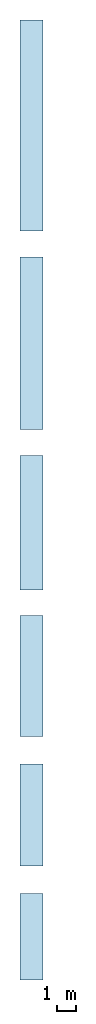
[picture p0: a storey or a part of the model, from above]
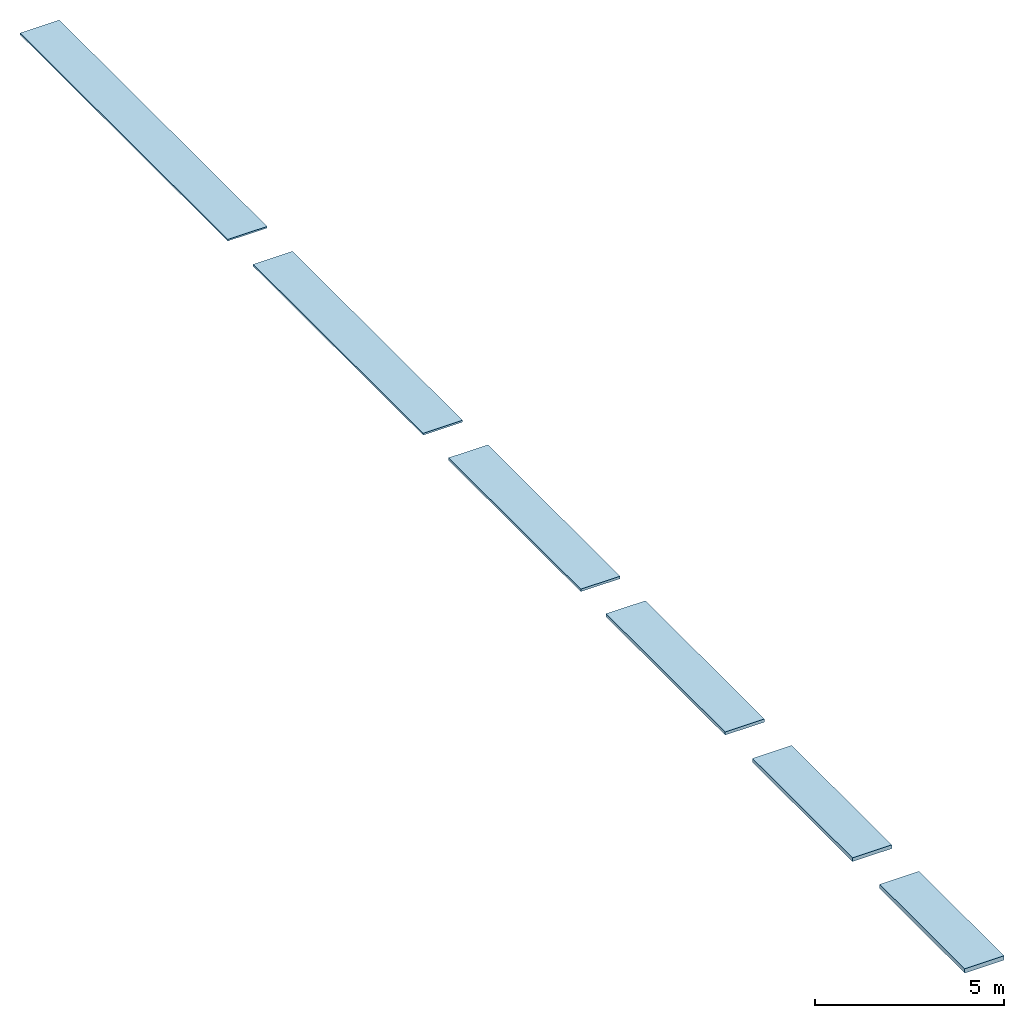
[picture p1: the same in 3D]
Properties of the parts of a building model (IFC2X3)

# File
Description: ViewDefinition [CoordinationView_V2.0]
File name: 0001
Time: 2018-02-28T13:13:18
Written by: The EXPRESS Data Manager Version 5.02.0100.07 : 28 Aug 2013
Made in: 20140606_1530(x64) - Exporter 15.6.0.0 - Alternate UI 15.6.0.0
Comment: STEP Physical File produced by: The EXPRESS Data Manager Version 5.02.0100.07 : 28 Aug 2013 * Module: EDMstepFileFactory/EDMstandAlone * Creation date: Wed Feb 28 13:13:18 2018 * Host: BRUTUS-02 * Database: C:\Users\MIGUEL~1\AppData\Local\Temp\{DA6E0581-9F91-44CB-83B0-A4054EFE4921}\ifc * Database version: 5507 * Database creation date: Wed Feb 28 13:13:18 2018 * Schema: IFC2X3 * Model: DataRepository.ifc * Model creation date: Wed Feb 28 13:13:18 2018 * Header model: DataRepository.ifc_HeaderModel * Header model creation date: Wed Feb 28 13:13:18 2018 * EDMuser: sdai-user * EDMgroup: sdai-group * License ID and type: 5605 : Permanent license. Expiry date: * EDMstepFileFactory options: 020000

# IfcProject, 0001
LongName: Project Name; Phase: Project Status

# IfcSite, Default
RefLatitude: 42, 21, 30, 344238; RefLongitude: -71, -3, -35, -194702; RefElevation: 0 mm
Other - Category: Project Information; Client Name: Owner; Project Address: ## Street City, State Zip; Project Issue Date: Issue Date; Project Name: Project Name; Project Number: 0001; Project Status: Project Status

# IfcBuilding
Pset_BuildingCommon - NumberOfStoreys: 1
Other - Category: Project Information; Client Name: Owner; Project Address: ## Street City, State Zip; Project Issue Date: Issue Date; Project Name: Project Name; Project Number: 0001; Project Status: Project Status

# IfcBuildingStorey, Референтни ниво
LongName: Референтни ниво; Elevation: 0 mm
Other - Category: Levels; Family Name: Level; Family: Level: 8mm Head; Family and Type: Level: 8mm Head; Type: Level: 8mm Head; Type Id: Level: 8mm Head
Constraints - Elevation: 0 mm; Elevation Base: Project Base Point
Dimensions - Computation Height: 0 mm
Identity Data - Building Story: yes; Name: Референтни ниво; Structural: no; Type Name: 8mm Head
Graphics - Color: 0; Line Pattern: Center; Line Weight: 1; Symbol at End 1 Default: no; Symbol at End 2 Default: yes

# IfcRoof: Basic Roof:Knauf Insulation - Unifit 035 - 100 mm - 100 x 6300 x 1200 mm, Basic Roof:Knauf Insulation - Unifit 035 - 100 mm - 100 x 6300 x 1200 mm:206765
In: Референтни ниво
Pset_RoofCommon - IsExternal: yes; Reference: Knauf Insulation - Unifit 035 - 100 mm - 100 x 6300 x 1200 mm; TotalArea: 7.56 m2; ProjectedArea: 7.56 m2
Pset_ManufacturerTypeInformation - Manufacturer: Knauf Insulation
Knauf Insulation Materijali – Krov - No.: 79
Constraints - Base Level: Level: Референтни ниво; Base Offset From Level: 0 mm; Cutoff Offset: 0 mm; Related to Mass: no; Room Bounding: yes
Construction - Fascia Depth: 0 mm; Rafter Cut: Plumb Cut; Maximum Ridge Height: 100 mm; Default Thickness: 100 mm
Dimensions - Slope: 0; Area: 7.56 m2; Thickness: 100 mm; Volume: 0.756 m3
Other - Category: Roofs; Family: Basic Roof: Knauf Insulation - Unifit 035 - 100 mm - 100 x 6300 x 1200 mm; Family and Type: Basic Roof: Knauf Insulation - Unifit 035 - 100 mm - 100 x 6300 x 1200 mm; Type: Basic Roof: Knauf Insulation - Unifit 035 - 100 mm - 100 x 6300 x 1200 mm; Type Id: Basic Roof: Knauf Insulation - Unifit 035 - 100 mm - 100 x 6300 x 1200 mm; Family Name: Basic Roof
Phasing - Phase Created: New Construction
Analytical Properties - Roughness: 3; Absorptance: 0.7; Heat Transfer Coefficient (U): 0.35; Thermal mass: 1420; Thermal Resistance (R): 2.85714
Graphics - Coarse Scale Fill Color: 3951475
Identity Data - Description: proizvod od staklene mineralne vune sa ECOSE® Technology. Pruža visoku zaštitu u pogledu termičke, zvučne i zaštite od požara. Proizvod je negoriv, otporan na visoke temperature, vodoodbojan, otporan na starenje i hemijski neutralan. Dimenzije se ne menjaju usled velikih temperaturnih promena.; KontaktE-mail: edin.dalifi@knaufinsulation.com; KontaktTelefon: +3811113310800; Manufacturer: Knauf Insulation; Model: Unifit 035; No.: 79; Type Comments: Namenjen je za primenu u kosim krovovima. Prilikom izolacije kosog krova, sa unutrašnje strane, UNIFIT 035 treba postaviti preko rogova i termoizolacije (najčešće kamene vune) koja je već ugrađena između rogova. Prilikom izvođenja izolacije sa spoljašnje strane, UNIFIT 035 treba postaviti između rogova. Sa spoljašnje strane postavlja se parna brana koja sprečava prodiranje unutrašnje vlage u izolacioni materijal.; Type Name: Knauf Insulation - Unifit 035 - 100 mm - 100 x 6300 x 1200 mm; URL: http://www.knaufinsulation.rs/sr/staklena-vuna/unifit-035

# IfcRoof: Basic Roof:Knauf Insulation - Unifit 035 - 120 mm - 120 x 5300 x 1200 mm, Basic Roof:Knauf Insulation - Unifit 035 - 120 mm - 120 x 5300 x 1200 mm:206897
In: Референтни ниво
Pset_RoofCommon - IsExternal: yes; Reference: Knauf Insulation - Unifit 035 - 120 mm - 120 x 5300 x 1200 mm; TotalArea: 6.36 m2; ProjectedArea: 6.36 m2
Pset_ManufacturerTypeInformation - Manufacturer: Knauf Insulation
Knauf Insulation Materijali – Krov - No.: 80
Constraints - Base Level: Level: Референтни ниво; Base Offset From Level: 0 mm; Cutoff Offset: 0 mm; Related to Mass: no; Room Bounding: yes
Construction - Fascia Depth: 0 mm; Rafter Cut: Plumb Cut; Maximum Ridge Height: 120 mm; Default Thickness: 120 mm
Dimensions - Slope: 0; Area: 6.36 m2; Thickness: 120 mm; Volume: 0.7632 m3
Other - Category: Roofs; Family: Basic Roof: Knauf Insulation - Unifit 035 - 120 mm - 120 x 5300 x 1200 mm; Family and Type: Basic Roof: Knauf Insulation - Unifit 035 - 120 mm - 120 x 5300 x 1200 mm; Type: Basic Roof: Knauf Insulation - Unifit 035 - 120 mm - 120 x 5300 x 1200 mm; Type Id: Basic Roof: Knauf Insulation - Unifit 035 - 120 mm - 120 x 5300 x 1200 mm; Family Name: Basic Roof
Phasing - Phase Created: New Construction
Analytical Properties - Roughness: 3; Absorptance: 0.7; Heat Transfer Coefficient (U): 0.291667; Thermal mass: 1704; Thermal Resistance (R): 3.42857
Graphics - Coarse Scale Fill Color: 3951475
Identity Data - Description: proizvod od staklene mineralne vune sa ECOSE® Technology. Pruža visoku zaštitu u pogledu termičke, zvučne i zaštite od požara. Proizvod je negoriv, otporan na visoke temperature, vodoodbojan, otporan na starenje i hemijski neutralan. Dimenzije se ne menjaju usled velikih temperaturnih promena.; KontaktE-mail: edin.dalifi@knaufinsulation.com; KontaktTelefon: +3811113310800; Manufacturer: Knauf Insulation; Model: Unifit 035; No.: 80; Type Comments: Namenjen je za primenu u kosim krovovima. Prilikom izolacije kosog krova, sa unutrašnje strane, UNIFIT 035 treba postaviti preko rogova i termoizolacije (najčešće kamene vune) koja je već ugrađena između rogova. Prilikom izvođenja izolacije sa spoljašnje strane, UNIFIT 035 treba postaviti između rogova. Sa spoljašnje strane postavlja se parna brana koja sprečava prodiranje unutrašnje vlage u izolacioni materijal.; Type Name: Knauf Insulation - Unifit 035 - 120 mm - 120 x 5300 x 1200 mm; URL: http://www.knaufinsulation.rs/sr/staklena-vuna/unifit-035

# IfcRoof: Basic Roof:Knauf Insulation - Unifit 035 - 140 mm - 140 x 4500 x 1200 mm, Basic Roof:Knauf Insulation - Unifit 035 - 140 mm - 140 x 4500 x 1200 mm:207101
In: Референтни ниво
Pset_RoofCommon - IsExternal: yes; Reference: Knauf Insulation - Unifit 035 - 140 mm - 140 x 4500 x 1200 mm; TotalArea: 5.4 m2; ProjectedArea: 5.4 m2
Pset_ManufacturerTypeInformation - Manufacturer: Knauf Insulation
Knauf Insulation Materijali – Krov - No.: 81
Constraints - Base Level: Level: Референтни ниво; Base Offset From Level: 0 mm; Cutoff Offset: 0 mm; Related to Mass: no; Room Bounding: yes
Construction - Fascia Depth: 0 mm; Rafter Cut: Plumb Cut; Maximum Ridge Height: 140 mm; Default Thickness: 140 mm
Dimensions - Slope: 0; Area: 5.4 m2; Thickness: 140 mm; Volume: 0.756 m3
Other - Category: Roofs; Family: Basic Roof: Knauf Insulation - Unifit 035 - 140 mm - 140 x 4500 x 1200 mm; Family and Type: Basic Roof: Knauf Insulation - Unifit 035 - 140 mm - 140 x 4500 x 1200 mm; Type: Basic Roof: Knauf Insulation - Unifit 035 - 140 mm - 140 x 4500 x 1200 mm; Type Id: Basic Roof: Knauf Insulation - Unifit 035 - 140 mm - 140 x 4500 x 1200 mm; Family Name: Basic Roof
Phasing - Phase Created: New Construction
Analytical Properties - Roughness: 3; Absorptance: 0.7; Heat Transfer Coefficient (U): 0.25; Thermal mass: 1988; Thermal Resistance (R): 4
Graphics - Coarse Scale Fill Color: 3951475
Identity Data - Description: proizvod od staklene mineralne vune sa ECOSE® Technology. Pruža visoku zaštitu u pogledu termičke, zvučne i zaštite od požara. Proizvod je negoriv, otporan na visoke temperature, vodoodbojan, otporan na starenje i hemijski neutralan. Dimenzije se ne menjaju usled velikih temperaturnih promena.; KontaktE-mail: edin.dalifi@knaufinsulation.com; KontaktTelefon: +3811113310800; Manufacturer: Knauf Insulation; Model: Unifit 035; No.: 81; Type Comments: Namenjen je za primenu u kosim krovovima. Prilikom izolacije kosog krova, sa unutrašnje strane, UNIFIT 035 treba postaviti preko rogova i termoizolacije (najčešće kamene vune) koja je već ugrađena između rogova. Prilikom izvođenja izolacije sa spoljašnje strane, UNIFIT 035 treba postaviti između rogova. Sa spoljašnje strane postavlja se parna brana koja sprečava prodiranje unutrašnje vlage u izolacioni materijal.; Type Name: Knauf Insulation - Unifit 035 - 140 mm - 140 x 4500 x 1200 mm; URL: http://www.knaufinsulation.rs/sr/staklena-vuna/unifit-035

# IfcRoof: Basic Roof:Knauf Insulation - Unifit 035 - 50 mm - 50 x 11000 x 1200 mm, Basic Roof:Knauf Insulation - Unifit 035 - 50 mm - 50 x 11000 x 1200 mm:206087
In: Референтни ниво
Pset_RoofCommon - Reference: Knauf Insulation - Unifit 035 - 50 mm - 50 x 11000 x 1200 mm; IsExternal: yes; TotalArea: 13.2 m2; ProjectedArea: 13.2 m2
Pset_ManufacturerTypeInformation - Manufacturer: Knauf Insulation
Knauf Insulation Materijali – Krov - No.: 76
Constraints - Base Level: Level: Референтни ниво; Base Offset From Level: 0 mm; Cutoff Offset: 0 mm; Related to Mass: no; Room Bounding: yes
Construction - Fascia Depth: 0 mm; Maximum Ridge Height: 50 mm; Rafter Cut: Plumb Cut; Default Thickness: 50 mm
Dimensions - Area: 13.2 m2; Slope: 0; Thickness: 50 mm; Volume: 0.66 m3
Other - Category: Roofs; Family: Basic Roof: Knauf Insulation - Unifit 035 - 50 mm - 50 x 11000 x 1200 mm; Family and Type: Basic Roof: Knauf Insulation - Unifit 035 - 50 mm - 50 x 11000 x 1200 mm; Type: Basic Roof: Knauf Insulation - Unifit 035 - 50 mm - 50 x 11000 x 1200 mm; Type Id: Basic Roof: Knauf Insulation - Unifit 035 - 50 mm - 50 x 11000 x 1200 mm; Family Name: Basic Roof
Phasing - Phase Created: New Construction
Analytical Properties - Absorptance: 0.7; Heat Transfer Coefficient (U): 0.7; Roughness: 3; Thermal mass: 710; Thermal Resistance (R): 1.42857
Graphics - Coarse Scale Fill Color: 3951475
Identity Data - Description: proizvod od staklene mineralne vune sa ECOSE® Technology. Pruža visoku zaštitu u pogledu termičke, zvučne i zaštite od požara. Proizvod je negoriv, otporan na visoke temperature, vodoodbojan, otporan na starenje i hemijski neutralan. Dimenzije se ne menjaju usled velikih temperaturnih promena.; KontaktE-mail: edin.dalifi@knaufinsulation.com; KontaktTelefon: +3811113310800; Manufacturer: Knauf Insulation; Model: Unifit 035; No.: 76; Type Comments: Namenjen je za primenu u kosim krovovima. Prilikom izolacije kosog krova, sa unutrašnje strane, UNIFIT 035 treba postaviti preko rogova i termoizolacije (najčešće kamene vune) koja je već ugrađena između rogova. Prilikom izvođenja izolacije sa spoljašnje strane, UNIFIT 035 treba postaviti između rogova. Sa spoljašnje strane postavlja se parna brana koja sprečava prodiranje unutrašnje vlage u izolacioni materijal.; Type Name: Knauf Insulation - Unifit 035 - 50 mm - 50 x 11000 x 1200 mm; URL: http://www.knaufinsulation.rs/sr/staklena-vuna/unifit-035

# IfcRoof: Basic Roof:Knauf Insulation - Unifit 035 - 60 mm - 60 x 9000 x 1200 mm, Basic Roof:Knauf Insulation - Unifit 035 - 60 mm - 60 x 9000 x 1200 mm:206390
In: Референтни ниво
Pset_RoofCommon - IsExternal: yes; Reference: Knauf Insulation - Unifit 035 - 60 mm - 60 x 9000 x 1200 mm; TotalArea: 10.8 m2; ProjectedArea: 10.8 m2
Pset_ManufacturerTypeInformation - Manufacturer: Knauf Insulation
Knauf Insulation Materijali – Krov - No.: 77
Constraints - Base Level: Level: Референтни ниво; Base Offset From Level: 0 mm; Cutoff Offset: 0 mm; Related to Mass: no; Room Bounding: yes
Construction - Fascia Depth: 0 mm; Rafter Cut: Plumb Cut; Maximum Ridge Height: 60 mm; Default Thickness: 60 mm
Dimensions - Slope: 0; Area: 10.8 m2; Thickness: 60 mm; Volume: 0.648 m3
Other - Category: Roofs; Family: Basic Roof: Knauf Insulation - Unifit 035 - 60 mm - 60 x 9000 x 1200 mm; Family and Type: Basic Roof: Knauf Insulation - Unifit 035 - 60 mm - 60 x 9000 x 1200 mm; Type: Basic Roof: Knauf Insulation - Unifit 035 - 60 mm - 60 x 9000 x 1200 mm; Type Id: Basic Roof: Knauf Insulation - Unifit 035 - 60 mm - 60 x 9000 x 1200 mm; Family Name: Basic Roof
Phasing - Phase Created: New Construction
Analytical Properties - Roughness: 3; Absorptance: 0.7; Heat Transfer Coefficient (U): 0.583333; Thermal mass: 852; Thermal Resistance (R): 1.71429
Graphics - Coarse Scale Fill Color: 3951475
Identity Data - Description: proizvod od staklene mineralne vune sa ECOSE® Technology. Pruža visoku zaštitu u pogledu termičke, zvučne i zaštite od požara. Proizvod je negoriv, otporan na visoke temperature, vodoodbojan, otporan na starenje i hemijski neutralan. Dimenzije se ne menjaju usled velikih temperaturnih promena.; KontaktE-mail: edin.dalifi@knaufinsulation.com; KontaktTelefon: +3811113310800; Manufacturer: Knauf Insulation; Model: Unifit 035; No.: 77; Type Comments: Namenjen je za primenu u kosim krovovima. Prilikom izolacije kosog krova, sa unutrašnje strane, UNIFIT 035 treba postaviti preko rogova i termoizolacije (najčešće kamene vune) koja je već ugrađena između rogova. Prilikom izvođenja izolacije sa spoljašnje strane, UNIFIT 035 treba postaviti između rogova. Sa spoljašnje strane postavlja se parna brana koja sprečava prodiranje unutrašnje vlage u izolacioni materijal.; Type Name: Knauf Insulation - Unifit 035 - 60 mm - 60 x 9000 x 1200 mm; URL: http://www.knaufinsulation.rs/sr/staklena-vuna/unifit-035

# IfcRoof: Basic Roof:Knauf Insulation - Unifit 035 - 80 mm - 80 x 7000 x 1200 mm, Basic Roof:Knauf Insulation - Unifit 035 - 80 mm - 80 x 7000 x 1200 mm:206632
In: Референтни ниво
Pset_RoofCommon - IsExternal: yes; Reference: Knauf Insulation - Unifit 035 - 80 mm - 80 x 7000 x 1200 mm; TotalArea: 8.4 m2; ProjectedArea: 8.4 m2
Pset_ManufacturerTypeInformation - Manufacturer: Knauf Insulation
Knauf Insulation Materijali – Krov - No.: 78
Constraints - Base Level: Level: Референтни ниво; Base Offset From Level: 0 mm; Cutoff Offset: 0 mm; Related to Mass: no; Room Bounding: yes
Construction - Fascia Depth: 0 mm; Rafter Cut: Plumb Cut; Maximum Ridge Height: 80 mm; Default Thickness: 80 mm
Dimensions - Slope: 0; Area: 8.4 m2; Thickness: 80 mm; Volume: 0.672 m3
Other - Category: Roofs; Family: Basic Roof: Knauf Insulation - Unifit 035 - 80 mm - 80 x 7000 x 1200 mm; Family and Type: Basic Roof: Knauf Insulation - Unifit 035 - 80 mm - 80 x 7000 x 1200 mm; Type: Basic Roof: Knauf Insulation - Unifit 035 - 80 mm - 80 x 7000 x 1200 mm; Type Id: Basic Roof: Knauf Insulation - Unifit 035 - 80 mm - 80 x 7000 x 1200 mm; Family Name: Basic Roof
Phasing - Phase Created: New Construction
Analytical Properties - Roughness: 3; Absorptance: 0.7; Heat Transfer Coefficient (U): 0.4375; Thermal mass: 1136; Thermal Resistance (R): 2.28571
Graphics - Coarse Scale Fill Color: 3951475
Identity Data - Description: proizvod od staklene mineralne vune sa ECOSE® Technology. Pruža visoku zaštitu u pogledu termičke, zvučne i zaštite od požara. Proizvod je negoriv, otporan na visoke temperature, vodoodbojan, otporan na starenje i hemijski neutralan. Dimenzije se ne menjaju usled velikih temperaturnih promena.; KontaktE-mail: edin.dalifi@knaufinsulation.com; KontaktTelefon: +3811113310800; Manufacturer: Knauf Insulation; Model: Unifit 035; No.: 78; Type Comments: Namenjen je za primenu u kosim krovovima. Prilikom izolacije kosog krova, sa unutrašnje strane, UNIFIT 035 treba postaviti preko rogova i termoizolacije (najčešće kamene vune) koja je već ugrađena između rogova. Prilikom izvođenja izolacije sa spoljašnje strane, UNIFIT 035 treba postaviti između rogova. Sa spoljašnje strane postavlja se parna brana koja sprečava prodiranje unutrašnje vlage u izolacioni materijal.; Type Name: Knauf Insulation - Unifit 035 - 80 mm - 80 x 7000 x 1200 mm; URL: http://www.knaufinsulation.rs/sr/staklena-vuna/unifit-035

# IfcSlab: Basic Roof:Knauf Insulation - Unifit 035 - 100 mm - 100 x 6300 x 1200 mm, Basic Roof:Knauf Insulation - Unifit 035 - 100 mm - 100 x 6300 x 1200 mm:206765
In: Референтни ниво
PredefinedType: ROOF; Material: Knauf Insulation - Unifit 035 - 100 mm - 100 x 6300 x 1200 mm 100 mm
Pset_SlabCommon - IsExternal: yes; LoadBearing: yes; PitchAngle: 0 deg; Reference: Knauf Insulation - Unifit 035 - 100 mm - 100 x 6300 x 1200 mm; ThermalTransmittance: 0.35 kg/K/s3
Pset_ManufacturerTypeInformation - Manufacturer: Knauf Insulation
Knauf Insulation Materijali – Krov - No.: 79

# IfcSlab: Basic Roof:Knauf Insulation - Unifit 035 - 120 mm - 120 x 5300 x 1200 mm, Basic Roof:Knauf Insulation - Unifit 035 - 120 mm - 120 x 5300 x 1200 mm:206897
In: Референтни ниво
PredefinedType: ROOF; Material: Knauf Insulation - Unifit 035 - 120 mm - 120 x 5300 x 1200 mm 120 mm
Pset_SlabCommon - IsExternal: yes; LoadBearing: yes; PitchAngle: 0 deg; Reference: Knauf Insulation - Unifit 035 - 120 mm - 120 x 5300 x 1200 mm; ThermalTransmittance: 0.291667 kg/K/s3
Pset_ManufacturerTypeInformation - Manufacturer: Knauf Insulation
Knauf Insulation Materijali – Krov - No.: 80

# IfcSlab: Basic Roof:Knauf Insulation - Unifit 035 - 140 mm - 140 x 4500 x 1200 mm, Basic Roof:Knauf Insulation - Unifit 035 - 140 mm - 140 x 4500 x 1200 mm:207101
In: Референтни ниво
PredefinedType: ROOF; Material: Knauf Insulation - Unifit 035 - 140 mm - 140 x 4500 x 1200 mm 140 mm
Pset_SlabCommon - IsExternal: yes; LoadBearing: yes; PitchAngle: 0 deg; Reference: Knauf Insulation - Unifit 035 - 140 mm - 140 x 4500 x 1200 mm; ThermalTransmittance: 0.25 kg/K/s3
Pset_ManufacturerTypeInformation - Manufacturer: Knauf Insulation
Knauf Insulation Materijali – Krov - No.: 81

# IfcSlab: Basic Roof:Knauf Insulation - Unifit 035 - 50 mm - 50 x 11000 x 1200 mm, Basic Roof:Knauf Insulation - Unifit 035 - 50 mm - 50 x 11000 x 1200 mm:206087
In: Референтни ниво
PredefinedType: ROOF; Material: Knauf Insulation - Unifit 035 - 50 mm - 50 x 11000 x 1200 mm 50 mm
Pset_SlabCommon - Reference: Knauf Insulation - Unifit 035 - 50 mm - 50 x 11000 x 1200 mm; IsExternal: yes; LoadBearing: yes; ThermalTransmittance: 0.7 kg/K/s3; PitchAngle: 0 deg
Pset_ManufacturerTypeInformation - Manufacturer: Knauf Insulation
Knauf Insulation Materijali – Krov - No.: 76

# IfcSlab: Basic Roof:Knauf Insulation - Unifit 035 - 60 mm - 60 x 9000 x 1200 mm, Basic Roof:Knauf Insulation - Unifit 035 - 60 mm - 60 x 9000 x 1200 mm:206390
In: Референтни ниво
PredefinedType: ROOF; Material: Knauf Insulation - Unifit 035 - 60 mm - 60 x 9000 x 1200 mm 60 mm
Pset_SlabCommon - IsExternal: yes; LoadBearing: yes; PitchAngle: 0 deg; Reference: Knauf Insulation - Unifit 035 - 60 mm - 60 x 9000 x 1200 mm; ThermalTransmittance: 0.583333 kg/K/s3
Pset_ManufacturerTypeInformation - Manufacturer: Knauf Insulation
Knauf Insulation Materijali – Krov - No.: 77

# IfcSlab: Basic Roof:Knauf Insulation - Unifit 035 - 80 mm - 80 x 7000 x 1200 mm, Basic Roof:Knauf Insulation - Unifit 035 - 80 mm - 80 x 7000 x 1200 mm:206632
In: Референтни ниво
PredefinedType: ROOF; Material: Knauf Insulation - Unifit 035 - 80 mm - 80 x 7000 x 1200 mm 80 mm
Pset_SlabCommon - IsExternal: yes; LoadBearing: yes; PitchAngle: 0 deg; Reference: Knauf Insulation - Unifit 035 - 80 mm - 80 x 7000 x 1200 mm; ThermalTransmittance: 0.4375 kg/K/s3
Pset_ManufacturerTypeInformation - Manufacturer: Knauf Insulation
Knauf Insulation Materijali – Krov - No.: 78
